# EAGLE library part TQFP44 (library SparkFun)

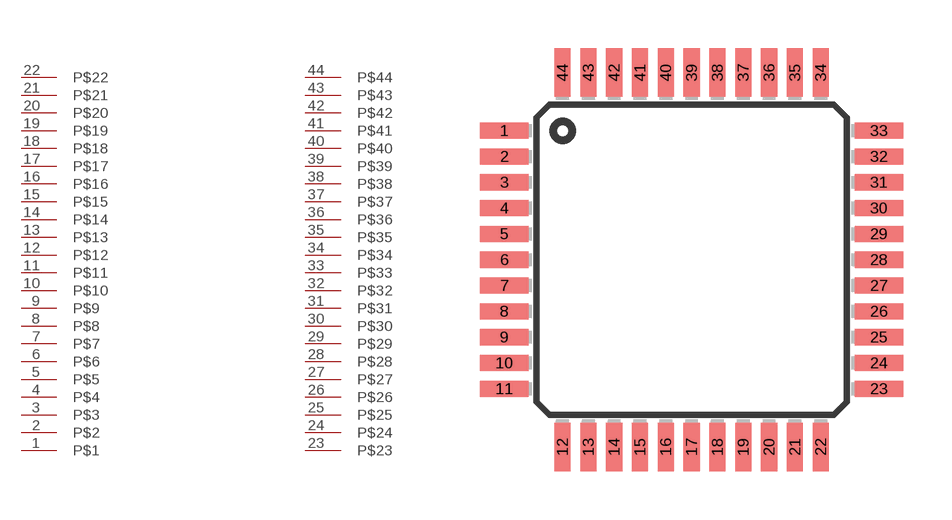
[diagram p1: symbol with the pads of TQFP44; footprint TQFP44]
Designator prefix -

## TQFP44  [TQFP44]
1  P$1
2  P$2
3  P$3
4  P$4
5  P$5
6  P$6
7  P$7
8  P$8
9  P$9
10  P$10
11  P$11
12  P$12
13  P$13
14  P$14
15  P$15
16  P$16
17  P$17
18  P$18
19  P$19
20  P$20
21  P$21
22  P$22
23  P$23
24  P$24
25  P$25
26  P$26
27  P$27
28  P$28
29  P$29
30  P$30
31  P$31
32  P$32
33  P$33
34  P$34
35  P$35
36  P$36
37  P$37
38  P$38
39  P$39
40  P$40
41  P$41
42  P$42
43  P$43
44  P$44

## Footprint TQFP44 (pad centres in mm)
smd 1.5 x 0.5: 1 -5.8,4; 2 -5.8,3.2; 3 -5.8,2.4; 4 -5.8,1.6; 5 -5.8,0.8; 6 -5.8,0; 7 -5.8,-0.8; 8 -5.8,-1.6; 9 -5.8,-2.4; 10 -5.8,-3.2; 11 -5.8,-4; 23 5.8,-4; 24 5.8,-3.2; 25 5.8,-2.4; 26 5.8,-1.6; 27 5.8,-0.8; 28 5.8,0; 29 5.8,0.8; 30 5.8,1.6; 31 5.8,2.4; 32 5.8,3.2; 33 5.8,4
smd 0.5 x 1.5: 12 -4,-5.8; 13 -3.2,-5.8; 14 -2.4,-5.8; 15 -1.6,-5.8; 16 -0.8,-5.8; 17 0,-5.8; 18 0.8,-5.8; 19 1.6,-5.8; 20 2.4,-5.8; 21 3.2,-5.8; 22 4,-5.8; 34 4,5.8; 35 3.2,5.8; 36 2.4,5.8; 37 1.6,5.8; 38 0.8,5.8; 39 0,5.8; 40 -0.8,5.8; 41 -1.6,5.8; 42 -2.4,5.8; 43 -3.2,5.8; 44 -4,5.8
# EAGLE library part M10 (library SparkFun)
Header 10 Standard 10-pin 0.1" header. Use with straight break away headers (SKU : PRT-00116), right angle break away headers (PRT-00553), swiss pins (PRT-00743), machine pins (PRT-00117), and female headers (PRT-00115).

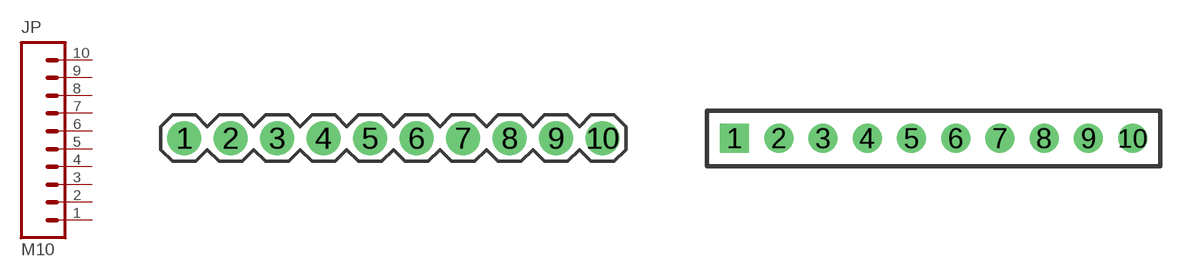
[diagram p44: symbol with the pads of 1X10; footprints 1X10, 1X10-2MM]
Designator prefix JP

## M10"  [1X10]
1  1  pas
2  2  pas
3  3  pas
4  4  pas
5  5  pas
6  6  pas
7  7  pas
8  8  pas
9  9  pas
10  10  pas

## M102MM  [1X10-2MM]
Pads as for 1X10

## M102MMSMD  [1X10-2MM-SMD]
Pads as for 1X10

## M10LOCK  [1X10_LOCK]
Pads as for 1X10

## M10LOCK_LONGPADS  [1X10_LOCK_LONGPADS]
Pads as for 1X10

## Footprint 1X10 (pad centres in mm)
drill 1.016 pad 1.88 round: 1 0,0; 2 2.54,0; 3 5.08,0; 4 7.62,0; 5 10.16,0; 6 12.7,0; 7 15.24,0; 8 17.78,0; 9 20.32,0; 10 22.86,0

## Footprint 1X10-2MM (pad centres in mm)
drill 0.8 square: 1 0,0
drill 0.8 round: 2 2,0; 3 4,0; 4 6,0; 5 8,0; 6 10,0; 7 12,0; 8 14,0; 9 16,0; 10 18,0

## Footprint 1X10-2MM-SMD (pad centres in mm)
smd 0.85 x 2.1: 1 0,-1.5; 2 2,1.5; 3 4,-1.5; 4 6,1.5; 5 8,-1.5; 6 10,1.5; 7 12,-1.5; 8 14,1.5; 9 16,-1.5; 10 18,1.5

## Footprint 1X10_LOCK (pad centres in mm)
drill 1.016 pad 1.88 round: 1 0,0.127; 2 2.54,-0.127; 3 5.08,0.127; 4 7.62,-0.127; 5 10.16,0.127; 6 12.7,-0.127; 7 15.24,0.127; 8 17.78,-0.127; 9 20.32,0.127; 10 22.86,-0.127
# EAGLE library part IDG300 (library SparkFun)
IDG300 This is a dual axis MEMs based gyroscope sensor from Invensense. The only gyro in currently available with two axis on one chip. Works very well. Schematic and footprint are not yet production proven. Spark Fun Electronics SKU : COM-00700

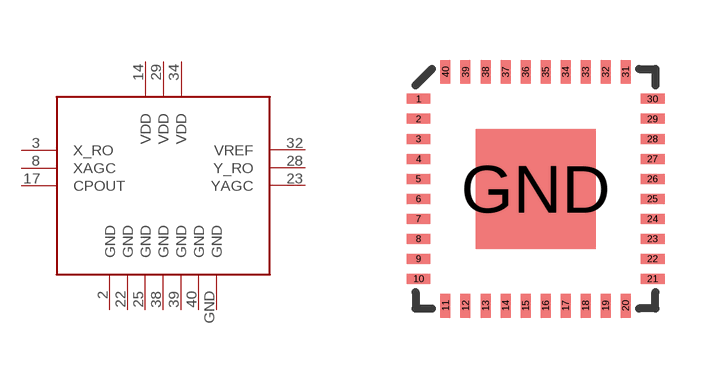
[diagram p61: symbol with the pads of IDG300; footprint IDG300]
Designator prefix -

## IDG300SMD  [IDG300]
2  GND
3  X_RO
8  XAGC
14  VDD
17  CPOUT
22  GND
23  YAGC
25  GND
28  Y_RO
29  VDD
32  VREF
34  VDD
38  GND
39  GND
40  GND
GND  GND

## Footprint IDG300 (pad centres in mm)
smd 0.6 x 0.25: 1 -2.925,2.25; 2 -2.925,1.75; 3 -2.925,1.25; 4 -2.925,0.75; 5 -2.925,0.25; 6 -2.925,-0.25; 7 -2.925,-0.75; 8 -2.925,-1.25; 9 -2.925,-1.75; 10 -2.925,-2.25; 21 2.925,-2.25; 22 2.925,-1.75; 23 2.925,-1.25; 24 2.925,-0.75; 25 2.925,-0.25; 26 2.925,0.25; 27 2.925,0.75; 28 2.925,1.25; 29 2.925,1.75; 30 2.925,2.25
smd 0.25 x 0.6: 11 -2.25,-2.925; 12 -1.75,-2.925; 13 -1.25,-2.925; 14 -0.75,-2.925; 15 -0.25,-2.925; 16 0.25,-2.925; 17 0.75,-2.925; 18 1.25,-2.925; 19 1.75,-2.925; 20 2.25,-2.925; 31 2.25,2.925; 32 1.75,2.925; 33 1.25,2.925; 34 0.75,2.925; 35 0.25,2.925; 36 -0.25,2.925; 37 -0.75,2.925; 38 -1.25,2.925; 39 -1.75,2.925; 40 -2.25,2.925
smd 3 x 3: GND 0,0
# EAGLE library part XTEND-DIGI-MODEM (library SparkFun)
Xtend Digi Modem WRL-09411

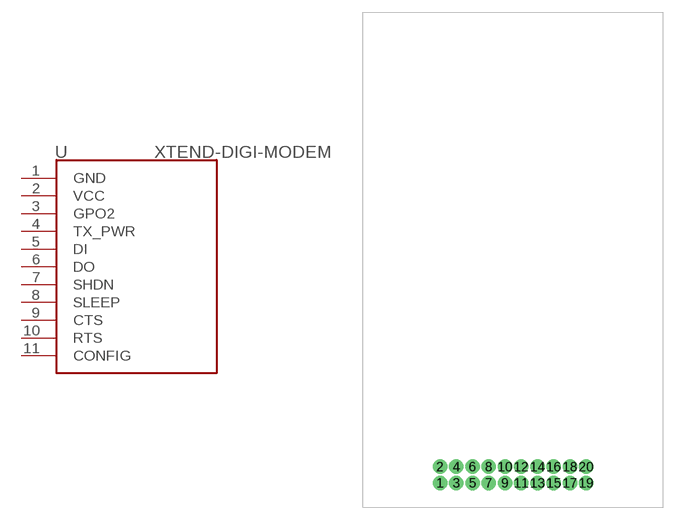
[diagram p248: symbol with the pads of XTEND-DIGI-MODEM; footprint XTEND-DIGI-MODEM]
Designator prefix -

## XTEND-DIGI-MODEM  [XTEND-DIGI-MODEM]
1  GND
2  VCC
3  GPO2
4  TX_PWR
5  DI
6  DO
7  SHDN
8  SLEEP
9  CTS
10  RTS
11  CONFIG

## Footprint XTEND-DIGI-MODEM (pad centres in mm)
Package for the Xtend Digi Modem 40 mile range
drill 1.016 pad 1.778 round: 1 -9,-27.5; 2 -9,-25.5; 3 -7,-27.5; 4 -7,-25.5; 5 -5,-27.5; 6 -5,-25.5; 7 -3,-27.5; 8 -3,-25.5; 9 -1,-27.5; 10 -1,-25.5; 11 1,-27.5; 12 1,-25.5; 13 3,-27.5; 14 3,-25.5; 15 5,-27.5; 16 5,-25.5; 17 7,-27.5; 18 7,-25.5; 19 9,-27.5; 20 9,-25.5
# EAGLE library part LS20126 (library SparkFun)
LS20126 20-Channel GPS Module SparkFun SKU# GPS-09838 The LOCOSYS LS20126 GPS smart antenna module is a high sensitivity, low power, SMD type, 20 channels with built-in magnetic sensor, 3-axial acceleration sensor L1 GPS receiver and 10mm patch antenna designed for portable applications.

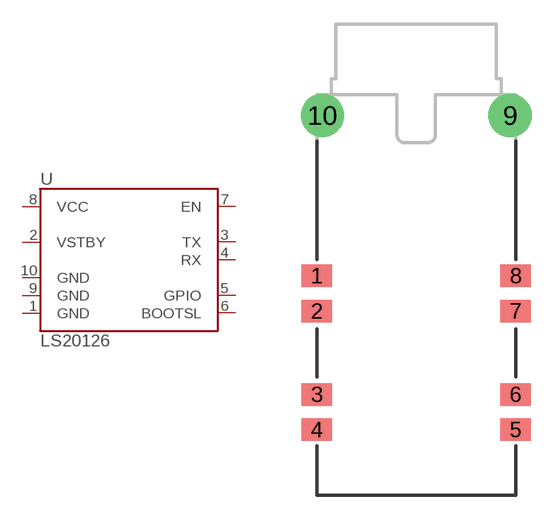
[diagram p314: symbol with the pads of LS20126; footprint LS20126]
Designator prefix U

## LS20126  [LS20126]
1  GND
2  VSTBY
3  TX
4  RX
5  GPIO
6  BOOTSL
7  EN
8  VCC
9  GND
10  GND

## Footprint LS20126 (pad centres in mm)
LS20126 GPS Receiver Package for LOCOSYS LS20126 GPS smart antenna module. SparkFun Sku# GPS-09838 Note: PCB cannot extend past top tPlace border @ 25mm Unproven!
smd 1.9 x 1.4: 1 -6.2,13.7; 2 -6.2,11.5; 3 -6.2,6.3; 4 -6.2,4.1; 5 6.2,4.1; 6 6.2,6.3; 7 6.2,11.5; 8 6.2,13.7
drill 1.8 round: 9 5.85,23.7; 10 -5.85,23.7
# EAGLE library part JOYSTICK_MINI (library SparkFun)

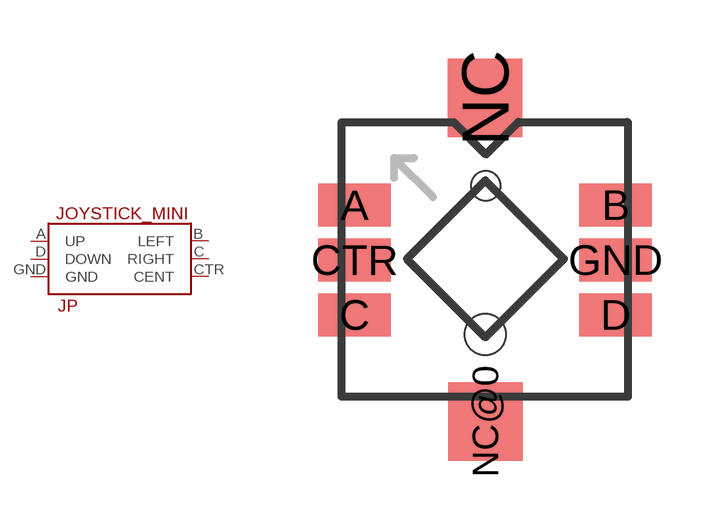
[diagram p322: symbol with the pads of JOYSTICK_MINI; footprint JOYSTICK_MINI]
Designator prefix JP

## JOYSTICK_MINI4UCON  [JOYSTICK_MINI]
A  UP
B  LEFT
C  RIGHT
CTR  CENT
D  DOWN
GND  GND

## Footprint JOYSTICK_MINI (pad centres in mm)
smd 1.85 x 1.1: A 0,2.8; B 6.65,2.8; C 0,0; CTR 0,1.4; D 6.65,0; GND 6.65,1.4
smd 1.9 x 2: NC 3.325,5.53; NC@0 3.33,-2.72
hole 0.75 at 3.34,3.295
hole 1.05 at 3.325,-0.5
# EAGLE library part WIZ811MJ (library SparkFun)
WIZnet W5100 Network Module with MagJack - WIZ811MJ WIZnet's WIZ811MJ is a breakout board for the W5100 embedded TCP/IP chip. Also included on the board is a RJ-45 MagJack Connector (RJ45 with X'FMR). See http://www.sparkfun.com/commerce/product_info.php?products_id=9473 for more documentation and info. **UNPROVEN

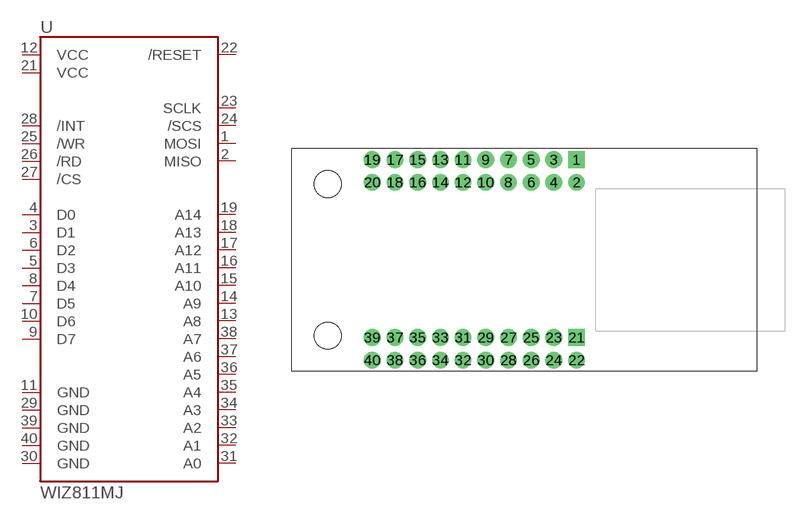
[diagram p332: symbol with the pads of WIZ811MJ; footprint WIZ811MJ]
Designator prefix U

## WIZ811MJ  [WIZ811MJ]
1  MOSI
2  MISO
3  D1
4  D0
5  D3
6  D2
7  D5
8  D4
9  D7
10  D6
11  GND
12  VCC
13  A8
14  A9
15  A10
16  A11
17  A12
18  A13
19  A14
21  VCC
22  /RESET
23  SCLK
24  /SCS
25  /WR
26  /RD
27  /CS
28  /INT
29  GND
30  GND
31  A0
32  A1
33  A2
34  A3
35  A4
36  A5
37  A6
38  A7
39  GND
40  GND

## Footprint WIZ811MJ (pad centres in mm)
WIZnet W5100 Network Module with MagJack - WIZ811MJ WIZnet's WIZ811MJ is a breakout board for the W5100 embedded TCP/IP chip. Also included on the board is a RJ-45 MagJack Connector (RJ45 with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
drill 1.02 pad 1.88 square: 1 0,0; 21 0,-19.92
drill 1.02 pad 1.88 round: 2 0,-2.54; 3 -2.54,0; 4 -2.54,-2.54; 5 -5.08,0; 6 -5.08,-2.54; 7 -7.62,0; 8 -7.62,-2.54; 9 -10.16,0; 10 -10.16,-2.54; 11 -12.7,0; 12 -12.7,-2.54; 13 -15.24,0; 14 -15.24,-2.54; 15 -17.78,0; 16 -17.78,-2.54; 17 -20.32,0; 18 -20.32,-2.54; 19 -22.86,0; 20 -22.86,-2.54; 22 0,-22.46; 23 -2.54,-19.92; 24 -2.54,-22.46; 25 -5.08,-19.92; 26 -5.08,-22.46; 27 -7.62,-19.92; 28 -7.62,-22.46; 29 -10.16,-19.92; 30 -10.16,-22.46; 31 -12.7,-19.92; 32 -12.7,-22.46; 33 -15.24,-19.92; 34 -15.24,-22.46; 35 -17.78,-19.92; 36 -17.78,-22.46; 37 -20.32,-19.92; 38 -20.32,-22.46; 39 -22.86,-19.92; 40 -22.86,-22.46
hole 3 at -27.86,-19.73
hole 3 at -27.86,-2.73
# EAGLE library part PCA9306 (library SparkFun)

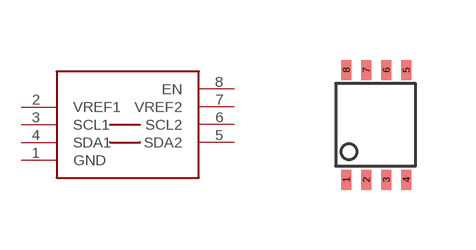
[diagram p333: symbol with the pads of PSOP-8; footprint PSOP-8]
Designator prefix -

## PCA9306  [PSOP-8]
1  GND
2  VREF1
3  SCL1
4  SDA1
5  SDA2
6  SCL2
7  VREF2
8  EN

## Footprint PSOP-8 (pad centres in mm)
smd 0.25 x 0.5: 1 -0.73,-1.37; 2 -0.23,-1.37; 3 0.27,-1.37; 4 0.77,-1.37; 5 0.77,1.38; 6 0.27,1.38; 7 -0.23,1.38; 8 -0.73,1.38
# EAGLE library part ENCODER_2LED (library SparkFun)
Illuminated Rotary Encoder w/ 2 LEDs

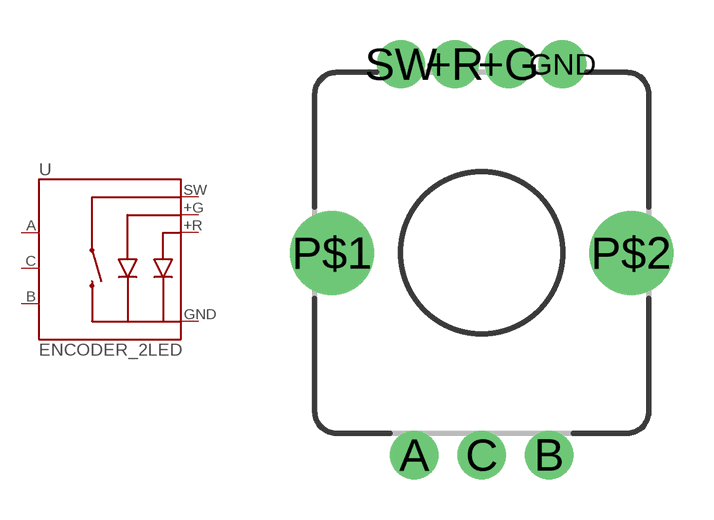
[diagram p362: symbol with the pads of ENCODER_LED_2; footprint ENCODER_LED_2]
Designator prefix U

## ENCODER_2LED  [ENCODER_LED_2]
+G  +G  pas
+R  +R  pas
A  A
B  B
C  C
GND  -  pas
SW  SW  pas

## Footprint ENCODER_LED_2 (pad centres in mm)
2-color Illuminated Rotary Encoder
drill 1.1 pad 1.778 round: +G 1,7; +R -1,7; GND 3,7; SW -3,7
drill 1.1 pad 1.8 round: A -2.5,-7.5; B 2.5,-7.5; C 0,-7.5
drill 2.1 round: P$1 -5.55,0; P$2 5.55,0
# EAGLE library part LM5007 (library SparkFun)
LM5007 High Voltage (80V) Step-down switching regulator http://www.national.com/ds/LM/LM5007.pdf

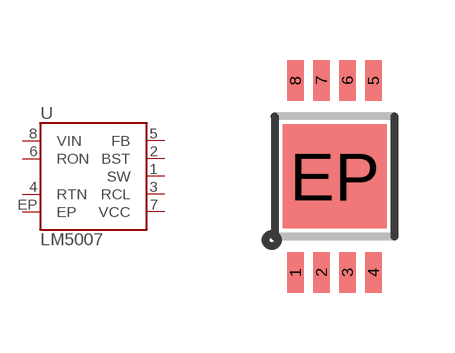
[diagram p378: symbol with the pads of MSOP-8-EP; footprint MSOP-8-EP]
Designator prefix U

## LM5007  [MSOP-8-EP]
1  SW
2  BST
3  RCL
4  RTN
5  FB
6  RON
7  VCC
8  VIN
EP  EP

## Footprint MSOP-8-EP (pad centres in mm)
smd 0.41 x 1.02: 1 -0.975,-2.4; 2 -0.325,-2.4; 3 0.325,-2.4; 4 0.975,-2.4; 5 0.975,2.4; 6 0.325,2.4; 7 -0.325,2.4; 8 -0.975,2.4
smd 2.6 x 2.6: EP 0,0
